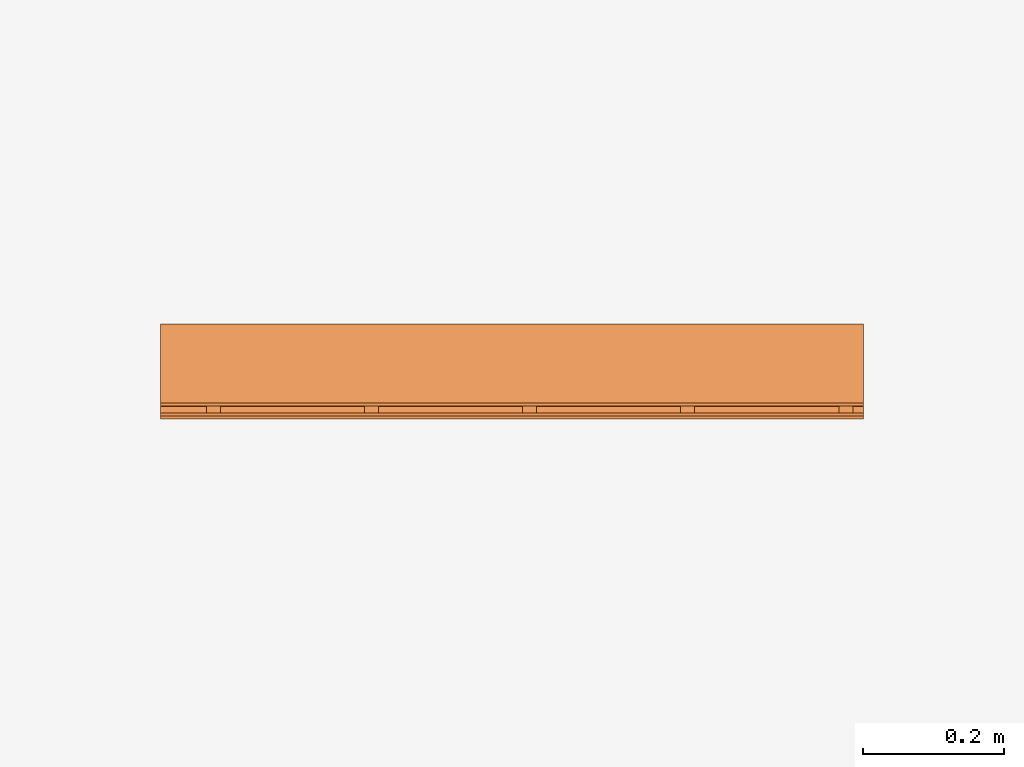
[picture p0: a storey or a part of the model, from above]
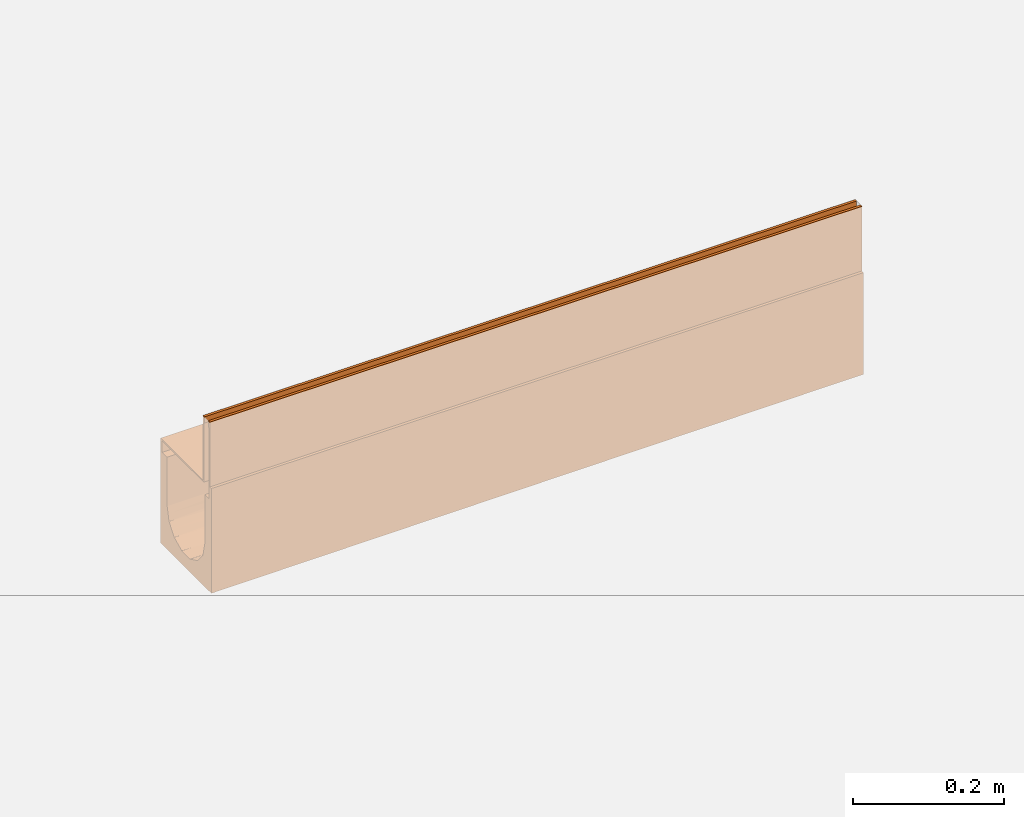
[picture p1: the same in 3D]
Properties of the parts of a building model (IFC2X3)

# File
Description: ViewDefinition [CoordinationView]
File name: 23004 - No 4 Sloping Channel - 1000mm LG - Invert Depth 145-150mm.ifc
Time: 2013-10-31T17:22:21
Written by: Autodesk Revit 2013
Made in: 20120221_2030(x64)

# IfcProject, Project Number
LongName: Project Name; Phase: Project Status

# IfcSite, Default
RefLatitude: 42, 21, 30, 344238; RefLongitude: -71, -3, -35, -194702; RefElevation: 0 mm

# IfcBuilding
Pset_BuildingCommon - NumberOfStoreys: 1
Other - Client Name: Owner; Project Issue Date: Issue Date; Project Name: Project Name; Project Number: Project Number; Project Address: ## Street City, State Zip; Project Status: Project Status

# IfcBuildingStorey, Level 1
LongName: Level 1; Elevation: 0 mm
Constraints - Elevation Base: 0; Elevation: 0 mm
Graphics - Color: 0; Symbol at End 1 Default: no; Line Pattern: Center; Symbol at End 2 Default: yes; Line Weight: 1; Symbol: M_Level Head - Circle: M_Level Head - Circle
Identity Data - Name: Level 1; Building Story: yes; Structural: no
Dimensions - Computation Height: 0 mm

# IfcBuildingElementProxy: 23004 - No 4 Sloping Channel - 1000mm LG - Invert Depth 145/150mm, Civil-Drainage-Channel-ACO-MultiDrain-M100D-Brickslot-Channel-System:23004 - No 4 Sloping Channel - 1000mm LG - Invert Depth 145/150mm:23004 - No 4 Sloping Channel - 1000mm LG - Invert Depth 145/150mm:196059
In: Level 1
Material: Steel, Galvanized, Vienite® Synthetic Resin Concrete
Dimensions - EndCap Position: 1000 mm; Length: 1000 mm; Brickslot Access Unit Void Bottom Depth: -6605 mm; Custom_Void_length: 0 mm; Brickslot Void Length: 1000 mm; Brickslot Void Depth: 0 mm; FloorCut_Length: -1000 mm; Brickslot Access Unit Void Depth: -6500 mm; Volume: 9201298 mm3; ShallowInvDepth: 55 mm; Access_Custom_Void_Length: 0 mm; Floor Cut Gap: 105 mm; EndCap_Height: 170 mm; SlopingOverallDepth: 165 mm; Brickslot Access Unit Floor Cut Length: 500 mm; Depth: 150 mm; SlopingEndInvertDepth: 100 mm; Length Drain: -1000 mm; FloorCut_Depth: 170 mm; ShallowOverallDepth: 75 mm; FloorCut_Width: 135 mm; SlopingInvertDepth: 95 mm; GratingLength: -1000 mm; SlopingEndOverallDepth: 170 mm; InvDepth: 80 mm
Construction - 23467_Load Class D400_Brickslot Access Unit_Galvanised Steel_500mm Long: no; 23404_Universal Endcap (Male End): no; 23466_Load Class D400_Brickslot Grating_Galvanized Steel_500mm Long: no; 23465_Load Class D400_Brickslot Grating_Galvanized Steel_1000mm Long: yes; 23462_Load Class C250_Brickslot Access Unit_Galvanised Steel_500mm Long: no; 23461_Load Class C250_Brickslot Grating_Galvanized Steel_500mm Long: no; 23404_Universal Endcap (Female End): no; 23460_Load Class C250_Brickslot Grating_Galvanized Steel_1000mm Long: no; Shallow Depth Channel with seal: no; Shallow Depth Channel: no; 23410_Sump Unit: no; Constant Depth Channel: no; Constant Depth Junction Channel: no; Sloping Channel: yes
Phasing - Phase Created: New Construction
Constraints - Level: Level: Level 1; Moves With Nearby Elements: no
Pset_BuildingElementProxyCommon - Reference: 23004 - No 4 Sloping Channel - 1000mm LG - Invert Depth 145/150mm
General - SerialNumber: 0; TagNumber: 0
Identity Data - Address: ACO Business Park, Hitchin Road, Shefford, Bedfordshire, United Kingdom SG17 5TE; Assembly Code: D2040; URL: www.aco.co.uk; OmniClass Number: 23.70.50.24; Fax: +44 (0)1462 815895; Telephone: +44 (0)1462 816666; Cost: 0; e-mail Technical: technical@aco.co.uk; Product brochure: http://www.aco.co.uk/download.php?id=173; Maintenance guidelines: http://www.aco.co.uk/download.php?id=173; Watermark 1: This file is the property of ACO Technologies PLC; Manufacturer: ACO Technologies plc - ACO Water Management Division; e-mail Sales: customersupport@aco.co.uk; Type Comments: ACO MultiDrain M100D No 4 Sloping Channel 1000mm Long; Assembly Description: Rain Water Drainage; Watermark 2: This file is water marked and users are prohibited to reproduce, adapt, distribute this information; Product Page URL: http://www.aco.co.uk/product_detail.php?id=58; OmniClass Title: Rainwater Removal; Watermarked With: BIM Manager Premium Suite; Model: ACO MultiDrain MD Brickslot- M100D; Product Code: 23004; Price: POA - contact ACO; Installation guidelines: http://www.aco.co.uk/download.php?id=173; Model Description: Channel drainage system
Green Building Properties - Channel Recyclable: Fully recyclable; Edge Rail Recyclable: Fully recyclable; Edge Rail Recycled Material Content: Between 40% - 90%; Channel Recycled Material Content: 20% minimum
Model Properties - Brickslot Grating Product code 23461: Load Class C250 - Brickslot Galvanised Steel - 500mm long x 105mm high - 10mm Slot - Intake area - 10000mm²/m -3.3 Kg; Brickslot Access Unit Product code 23467: Load Class D400 - Brickslot Access Unit Galvanised Steel - 500mm long x 105mm high - 10mm Slot - Intake area - 10000mm²/m - 6.4 Kg; Brickslot Grating Product code 23460: Load Class C250 - Brickslot Galvanised Steel - 1000mm long x 105mm high - 10mm Slot - Intake area - 10000mm²/m - 6.6 Kg; Brickslot Grating Product code 23466: Load Class D400 - Brickslot Galvanised Steel - 500mm long x 105mm high - 10mm Slot - Intake area - 10000mm²/m - 3.3 Kg; Brickslot Grating Product code 23465: Load Class D400 - Brickslot Galvanised Steel - 1000mm long x 105mm high - 10mm Slot - Intake area - 10000mm²/m - 6.6 Kg; End Cap Product code 23404: No 306 Universal End Cap - 135mm wide x 300mm long - Spigot Ø110mm x 50mm long - Silver - Polypropylene - 0.16kg; Brickslot Access Unit Product code 23462: Load Class C250 - Brickslot Access Unit Galvanised Steel - 500mm long x 105mm high - 10mm Slot - Intake area - 10000mm²/m - 6.4 Kg
Data - Invert Depth: 145mm/150mm; Concrete Surround Volume - Load Class A 15 - Concrete Pavement: N/A; Channel C.S.A: N/A; Hydraulic Performance: http://www.aco.co.uk/download.php?id=173; Product Weight: 14.4 Kg; Pre-formed Outlet Ø: N/A; Load Class: A 15 - D 400; Concrete Surround Volume - Load Class B 125 - C 250 - Concrete Pavement: N/A; Product Dimensions: 1000mm x 135mm x 165mm/170mm (LxWxH); Concrete Surround Volume - Load Class D 400 - Concrete Pavement: N/A; ACO Hydraulic Design Software: http://www.acodesign.co.uk; Product Standard: BS EN 1433:2002, CE marked; Installation - Concrete Grade: Refer to brochure
Materials and Finishes - Channel Colour: Brown; Channel Material: Vienite® Synthetic Resin Concrete; Edge Rail Material: Steel; Edge Rail Colour: Silver; Edge Rail Finish: Pre-galvanised
Other - Watermarked By: www.aco.co.uk; Revision: 1; Created By: www.aco.co.uk

# IfcOpeningElement: Recess (2)
In: Level 1
Dimensions - Perimeter: 20000 mm; Thickness: 1000 mm; Volume: 24975160000 mm3; Area: 25000000 mm2
Constraints - Level: Level: Level 1; Related to Mass: no; Room Bounding: yes; Height Offset From Level: 0 mm
Structural - Structural: no; Enable Analytical Model: no
Phasing - Phase Created: New Construction
Materials and Finishes - Structural Material: Earth
Analytical Properties - Thermal Resistance (R): 1.19474; Absorptance: 0.1; Thermal mass: 1359800; Roughness: 1; Heat Transfer Coefficient (U): 0.837
Construction - Function: 0; Default Thickness: 1000 mm
Graphics - Coarse Scale Fill Color: 0

# IfcSlab: Floor:Generic Floor - 1000mm, Floor:Generic Floor - 1000mm:193825
In: Level 1
PredefinedType: FLOOR; Material: Earth 1000 mm
Dimensions - Perimeter: 20000 mm; Thickness: 1000 mm; Volume: 24975160000 mm3; Area: 25000000 mm2
Constraints - Level: Level: Level 1; Related to Mass: no; Room Bounding: yes; Height Offset From Level: 0 mm
Structural - Structural: no; Enable Analytical Model: no
Phasing - Phase Created: New Construction
Pset_SlabCommon - Reference: Generic Floor - 1000mm; IsExternal: no; LoadBearing: yes
Materials and Finishes - Structural Material: Earth
Analytical Properties - Thermal Resistance (R): 1.19474; Absorptance: 0.1; Thermal mass: 1359800; Roughness: 1; Heat Transfer Coefficient (U): 0.837
Construction - Function: 0; Default Thickness: 1000 mm
Graphics - Coarse Scale Fill Color: 0
